VERSION 5.7 ;
  NOWIREEXTENSIONATPIN ON ;
  DIVIDERCHAR "/" ;
  BUSBITCHARS "[]" ;
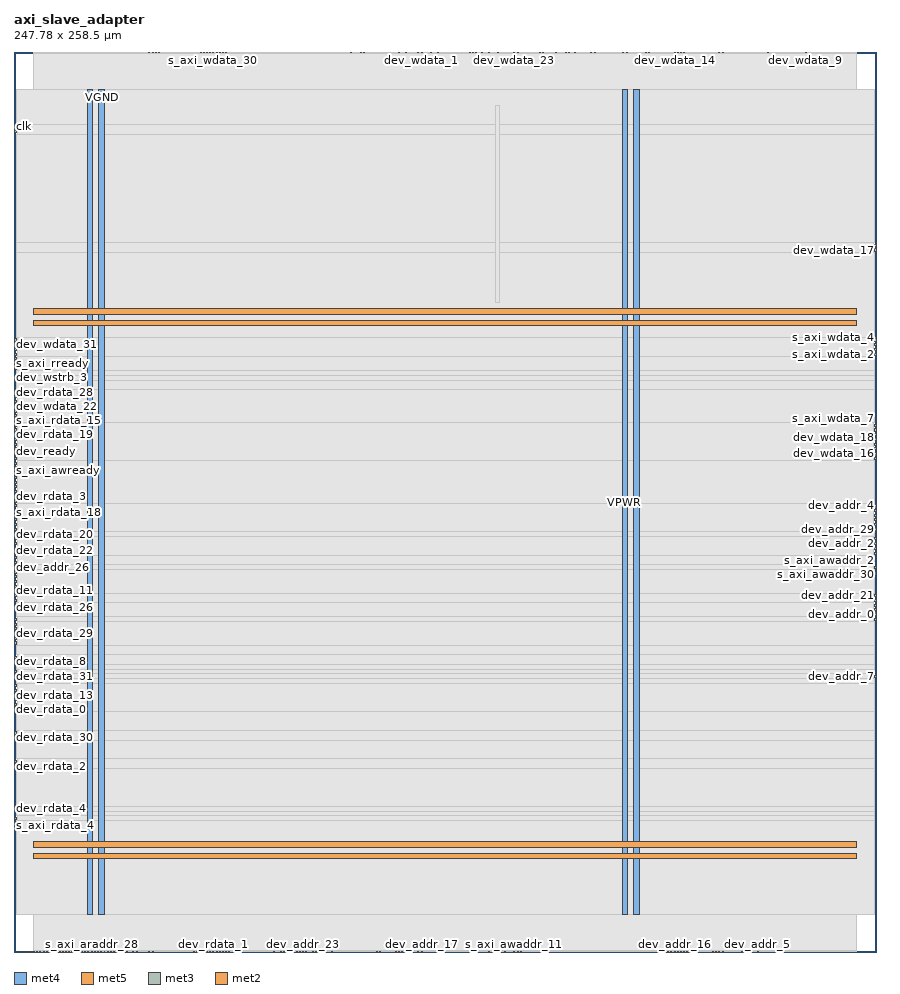
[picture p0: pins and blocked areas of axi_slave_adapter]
MACRO axi_slave_adapter
  CLASS BLOCK ;
  FOREIGN axi_slave_adapter ;
  ORIGIN 0.000 0.000 ;
  SIZE 247.780 BY 258.500 ;
  PIN VGND
    DIRECTION INOUT ;
    USE GROUND ;
    PORT
      LAYER met4 ;
        RECT 24.340 10.640 25.940 247.760 ;
    END
    PORT
      LAYER met4 ;
        RECT 177.940 10.640 179.540 247.760 ;
    END
    PORT
      LAYER met5 ;
        RECT 5.520 30.030 241.960 31.630 ;
    END
    PORT
      LAYER met5 ;
        RECT 5.520 183.210 241.960 184.810 ;
    END
  END VGND
  PIN VPWR
    DIRECTION INOUT ;
    USE POWER ;
    PORT
      LAYER met4 ;
        RECT 21.040 10.640 22.640 247.760 ;
    END
    PORT
      LAYER met4 ;
        RECT 174.640 10.640 176.240 247.760 ;
    END
    PORT
      LAYER met5 ;
        RECT 5.520 26.730 241.960 28.330 ;
    END
    PORT
      LAYER met5 ;
        RECT 5.520 179.910 241.960 181.510 ;
    END
  END VPWR
  PIN clk
    DIRECTION INPUT ;
    USE SIGNAL ;
    ANTENNAGATEAREA 1.286700 ;
    ANTENNADIFFAREA 0.434700 ;
    PORT
      LAYER met3 ;
        RECT 0.000 236.680 0.600 237.280 ;
    END
  END clk
  PIN dev_addr_0
    DIRECTION OUTPUT ;
    USE SIGNAL ;
    ANTENNAGATEAREA 0.434700 ;
    ANTENNADIFFAREA 1.137600 ;
    PORT
      LAYER met3 ;
        RECT 247.180 96.600 247.780 97.200 ;
    END
  END dev_addr_0
  PIN dev_addr_1
    DIRECTION OUTPUT ;
    USE SIGNAL ;
    ANTENNAGATEAREA 0.434700 ;
    ANTENNADIFFAREA 1.137600 ;
    PORT
      LAYER met2 ;
        RECT 200.650 0.000 200.930 0.280 ;
    END
  END dev_addr_1
  PIN dev_addr_10
    DIRECTION OUTPUT ;
    USE SIGNAL ;
    ANTENNAGATEAREA 0.434700 ;
    ANTENNADIFFAREA 1.137600 ;
    PORT
      LAYER met2 ;
        RECT 194.210 0.000 194.490 0.280 ;
    END
  END dev_addr_10
  PIN dev_addr_11
    DIRECTION OUTPUT ;
    USE SIGNAL ;
    ANTENNAGATEAREA 0.434700 ;
    ANTENNADIFFAREA 1.137600 ;
    PORT
      LAYER met2 ;
        RECT 140.850 0.000 141.130 0.280 ;
    END
  END dev_addr_11
  PIN dev_addr_12
    DIRECTION OUTPUT ;
    USE SIGNAL ;
    ANTENNAGATEAREA 0.434700 ;
    ANTENNADIFFAREA 1.137600 ;
    PORT
      LAYER met2 ;
        RECT 190.530 0.000 190.810 0.280 ;
    END
  END dev_addr_12
  PIN dev_addr_13
    DIRECTION OUTPUT ;
    USE SIGNAL ;
    ANTENNAGATEAREA 0.434700 ;
    ANTENNADIFFAREA 1.137600 ;
    PORT
      LAYER met2 ;
        RECT 74.610 0.000 74.890 0.280 ;
    END
  END dev_addr_13
  PIN dev_addr_14
    DIRECTION OUTPUT ;
    USE SIGNAL ;
    ANTENNAGATEAREA 0.434700 ;
    ANTENNADIFFAREA 1.137600 ;
    PORT
      LAYER met2 ;
        RECT 104.050 0.000 104.330 0.280 ;
    END
  END dev_addr_14
  PIN dev_addr_15
    DIRECTION OUTPUT ;
    USE SIGNAL ;
    ANTENNAGATEAREA 0.434700 ;
    ANTENNADIFFAREA 1.137600 ;
    PORT
      LAYER met2 ;
        RECT 136.250 0.000 136.530 0.280 ;
    END
  END dev_addr_15
  PIN dev_addr_16
    DIRECTION OUTPUT ;
    USE SIGNAL ;
    ANTENNAGATEAREA 0.434700 ;
    ANTENNADIFFAREA 1.137600 ;
    PORT
      LAYER met2 ;
        RECT 189.610 0.000 189.890 0.280 ;
    END
  END dev_addr_16
  PIN dev_addr_17
    DIRECTION OUTPUT ;
    USE SIGNAL ;
    ANTENNAGATEAREA 0.434700 ;
    ANTENNADIFFAREA 1.137600 ;
    PORT
      LAYER met2 ;
        RECT 116.930 0.000 117.210 0.280 ;
    END
  END dev_addr_17
  PIN dev_addr_18
    DIRECTION OUTPUT ;
    USE SIGNAL ;
    ANTENNAGATEAREA 0.434700 ;
    ANTENNADIFFAREA 1.137600 ;
    PORT
      LAYER met2 ;
        RECT 188.690 0.000 188.970 0.280 ;
    END
  END dev_addr_18
  PIN dev_addr_19
    DIRECTION OUTPUT ;
    USE SIGNAL ;
    ANTENNAGATEAREA 0.434700 ;
    ANTENNADIFFAREA 1.137600 ;
    PORT
      LAYER met2 ;
        RECT 203.410 0.000 203.690 0.280 ;
    END
  END dev_addr_19
  PIN dev_addr_2
    DIRECTION OUTPUT ;
    USE SIGNAL ;
    ANTENNAGATEAREA 0.434700 ;
    ANTENNADIFFAREA 1.137600 ;
    PORT
      LAYER met3 ;
        RECT 247.180 117.000 247.780 117.600 ;
    END
  END dev_addr_2
  PIN dev_addr_20
    DIRECTION OUTPUT ;
    USE SIGNAL ;
    ANTENNAGATEAREA 0.434700 ;
    ANTENNADIFFAREA 1.137600 ;
    PORT
      LAYER met2 ;
        RECT 111.410 0.000 111.690 0.280 ;
    END
  END dev_addr_20
  PIN dev_addr_21
    DIRECTION OUTPUT ;
    USE SIGNAL ;
    ANTENNAGATEAREA 0.434700 ;
    ANTENNADIFFAREA 1.137600 ;
    PORT
      LAYER met3 ;
        RECT 247.180 102.040 247.780 102.640 ;
    END
  END dev_addr_21
  PIN dev_addr_22
    DIRECTION OUTPUT ;
    USE SIGNAL ;
    ANTENNAGATEAREA 0.434700 ;
    ANTENNADIFFAREA 1.137600 ;
    PORT
      LAYER met2 ;
        RECT 122.450 0.000 122.730 0.280 ;
    END
  END dev_addr_22
  PIN dev_addr_23
    DIRECTION OUTPUT ;
    USE SIGNAL ;
    ANTENNAGATEAREA 0.434700 ;
    ANTENNADIFFAREA 1.137600 ;
    PORT
      LAYER met2 ;
        RECT 82.890 0.000 83.170 0.280 ;
    END
  END dev_addr_23
  PIN dev_addr_24
    DIRECTION OUTPUT ;
    USE SIGNAL ;
    ANTENNAGATEAREA 0.434700 ;
    ANTENNADIFFAREA 1.137600 ;
    PORT
      LAYER met2 ;
        RECT 76.450 0.000 76.730 0.280 ;
    END
  END dev_addr_24
  PIN dev_addr_25
    DIRECTION OUTPUT ;
    USE SIGNAL ;
    ANTENNAGATEAREA 0.434700 ;
    ANTENNADIFFAREA 1.137600 ;
    PORT
      LAYER met2 ;
        RECT 86.570 0.000 86.850 0.280 ;
    END
  END dev_addr_25
  PIN dev_addr_26
    DIRECTION OUTPUT ;
    USE SIGNAL ;
    ANTENNAGATEAREA 0.434700 ;
    ANTENNADIFFAREA 1.137600 ;
    PORT
      LAYER met3 ;
        RECT 0.000 110.200 0.600 110.800 ;
    END
  END dev_addr_26
  PIN dev_addr_27
    DIRECTION OUTPUT ;
    USE SIGNAL ;
    ANTENNAGATEAREA 0.434700 ;
    ANTENNADIFFAREA 1.137600 ;
    PORT
      LAYER met2 ;
        RECT 193.290 0.000 193.570 0.280 ;
    END
  END dev_addr_27
  PIN dev_addr_28
    DIRECTION OUTPUT ;
    USE SIGNAL ;
    ANTENNAGATEAREA 0.434700 ;
    ANTENNADIFFAREA 1.137600 ;
    PORT
      LAYER met3 ;
        RECT 0.000 123.800 0.600 124.400 ;
    END
  END dev_addr_28
  PIN dev_addr_29
    DIRECTION OUTPUT ;
    USE SIGNAL ;
    ANTENNAGATEAREA 0.434700 ;
    ANTENNADIFFAREA 1.137600 ;
    PORT
      LAYER met3 ;
        RECT 247.180 121.080 247.780 121.680 ;
    END
  END dev_addr_29
  PIN dev_addr_3
    DIRECTION OUTPUT ;
    USE SIGNAL ;
    ANTENNAGATEAREA 0.434700 ;
    ANTENNADIFFAREA 1.137600 ;
    PORT
      LAYER met3 ;
        RECT 247.180 100.680 247.780 101.280 ;
    END
  END dev_addr_3
  PIN dev_addr_30
    DIRECTION OUTPUT ;
    USE SIGNAL ;
    ANTENNAGATEAREA 0.434700 ;
    ANTENNADIFFAREA 1.137600 ;
    PORT
      LAYER met3 ;
        RECT 247.180 115.640 247.780 116.240 ;
    END
  END dev_addr_30
  PIN dev_addr_31
    DIRECTION OUTPUT ;
    USE SIGNAL ;
    ANTENNAGATEAREA 0.434700 ;
    ANTENNADIFFAREA 1.137600 ;
    PORT
      LAYER met3 ;
        RECT 247.180 126.520 247.780 127.120 ;
    END
  END dev_addr_31
  PIN dev_addr_4
    DIRECTION OUTPUT ;
    USE SIGNAL ;
    ANTENNAGATEAREA 0.434700 ;
    ANTENNADIFFAREA 1.137600 ;
    PORT
      LAYER met3 ;
        RECT 247.180 127.880 247.780 128.480 ;
    END
  END dev_addr_4
  PIN dev_addr_5
    DIRECTION OUTPUT ;
    USE SIGNAL ;
    ANTENNAGATEAREA 0.434700 ;
    ANTENNADIFFAREA 1.137600 ;
    PORT
      LAYER met2 ;
        RECT 213.530 0.000 213.810 0.280 ;
    END
  END dev_addr_5
  PIN dev_addr_6
    DIRECTION OUTPUT ;
    USE SIGNAL ;
    ANTENNAGATEAREA 0.434700 ;
    ANTENNADIFFAREA 1.137600 ;
    PORT
      LAYER met2 ;
        RECT 144.530 0.000 144.810 0.280 ;
    END
  END dev_addr_6
  PIN dev_addr_7
    DIRECTION OUTPUT ;
    USE SIGNAL ;
    ANTENNAGATEAREA 0.434700 ;
    ANTENNADIFFAREA 1.137600 ;
    PORT
      LAYER met3 ;
        RECT 247.180 78.920 247.780 79.520 ;
    END
  END dev_addr_7
  PIN dev_addr_8
    DIRECTION OUTPUT ;
    USE SIGNAL ;
    ANTENNAGATEAREA 0.434700 ;
    ANTENNADIFFAREA 1.137600 ;
    PORT
      LAYER met2 ;
        RECT 110.490 0.000 110.770 0.280 ;
    END
  END dev_addr_8
  PIN dev_addr_9
    DIRECTION OUTPUT ;
    USE SIGNAL ;
    ANTENNAGATEAREA 0.434700 ;
    ANTENNADIFFAREA 1.137600 ;
    PORT
      LAYER met2 ;
        RECT 77.370 0.000 77.650 0.280 ;
    END
  END dev_addr_9
  PIN dev_rdata_0
    DIRECTION INPUT ;
    USE SIGNAL ;
    ANTENNAGATEAREA 0.647700 ;
    ANTENNADIFFAREA 0.434700 ;
    PORT
      LAYER met3 ;
        RECT 0.000 69.400 0.600 70.000 ;
    END
  END dev_rdata_0
  PIN dev_rdata_1
    DIRECTION INPUT ;
    USE SIGNAL ;
    ANTENNAGATEAREA 0.647700 ;
    ANTENNADIFFAREA 0.434700 ;
    PORT
      LAYER met2 ;
        RECT 57.130 0.000 57.410 0.280 ;
    END
  END dev_rdata_1
  PIN dev_rdata_10
    DIRECTION INPUT ;
    USE SIGNAL ;
    ANTENNAGATEAREA 0.647700 ;
    ANTENNADIFFAREA 0.434700 ;
    PORT
      LAYER met2 ;
        RECT 58.970 0.000 59.250 0.280 ;
    END
  END dev_rdata_10
  PIN dev_rdata_11
    DIRECTION INPUT ;
    USE SIGNAL ;
    ANTENNAGATEAREA 0.647700 ;
    ANTENNADIFFAREA 0.434700 ;
    PORT
      LAYER met3 ;
        RECT 0.000 103.400 0.600 104.000 ;
    END
  END dev_rdata_11
  PIN dev_rdata_12
    DIRECTION INPUT ;
    USE SIGNAL ;
    ANTENNAGATEAREA 0.647700 ;
    ANTENNADIFFAREA 0.434700 ;
    PORT
      LAYER met3 ;
        RECT 0.000 125.160 0.600 125.760 ;
    END
  END dev_rdata_12
  PIN dev_rdata_13
    DIRECTION INPUT ;
    USE SIGNAL ;
    ANTENNAGATEAREA 0.647700 ;
    ANTENNADIFFAREA 0.434700 ;
    PORT
      LAYER met3 ;
        RECT 0.000 73.480 0.600 74.080 ;
    END
  END dev_rdata_13
  PIN dev_rdata_14
    DIRECTION INPUT ;
    USE SIGNAL ;
    ANTENNAGATEAREA 0.647700 ;
    ANTENNADIFFAREA 0.434700 ;
    PORT
      LAYER met2 ;
        RECT 35.050 0.000 35.330 0.280 ;
    END
  END dev_rdata_14
  PIN dev_rdata_15
    DIRECTION INPUT ;
    USE SIGNAL ;
    ANTENNAGATEAREA 0.647700 ;
    ANTENNADIFFAREA 0.434700 ;
    PORT
      LAYER met3 ;
        RECT 0.000 149.640 0.600 150.240 ;
    END
  END dev_rdata_15
  PIN dev_rdata_16
    DIRECTION INPUT ;
    USE SIGNAL ;
    ANTENNAGATEAREA 0.647700 ;
    ANTENNADIFFAREA 0.434700 ;
    PORT
      LAYER met2 ;
        RECT 51.610 0.000 51.890 0.280 ;
    END
  END dev_rdata_16
  PIN dev_rdata_17
    DIRECTION INPUT ;
    USE SIGNAL ;
    ANTENNAGATEAREA 0.647700 ;
    ANTENNADIFFAREA 0.434700 ;
    PORT
      LAYER met2 ;
        RECT 21.250 0.000 21.530 0.280 ;
    END
  END dev_rdata_17
  PIN dev_rdata_18
    DIRECTION INPUT ;
    USE SIGNAL ;
    ANTENNAGATEAREA 0.647700 ;
    ANTENNADIFFAREA 0.434700 ;
    PORT
      LAYER met3 ;
        RECT 0.000 126.520 0.600 127.120 ;
    END
  END dev_rdata_18
  PIN dev_rdata_19
    DIRECTION INPUT ;
    USE SIGNAL ;
    ANTENNAGATEAREA 0.647700 ;
    ANTENNADIFFAREA 0.434700 ;
    PORT
      LAYER met3 ;
        RECT 0.000 148.280 0.600 148.880 ;
    END
  END dev_rdata_19
  PIN dev_rdata_2
    DIRECTION INPUT ;
    USE SIGNAL ;
    ANTENNAGATEAREA 0.647700 ;
    ANTENNADIFFAREA 0.434700 ;
    PORT
      LAYER met3 ;
        RECT 0.000 53.080 0.600 53.680 ;
    END
  END dev_rdata_2
  PIN dev_rdata_20
    DIRECTION INPUT ;
    USE SIGNAL ;
    ANTENNAGATEAREA 0.647700 ;
    ANTENNADIFFAREA 0.434700 ;
    PORT
      LAYER met3 ;
        RECT 0.000 119.720 0.600 120.320 ;
    END
  END dev_rdata_20
  PIN dev_rdata_21
    DIRECTION INPUT ;
    USE SIGNAL ;
    ANTENNAGATEAREA 0.647700 ;
    ANTENNADIFFAREA 0.434700 ;
    PORT
      LAYER met2 ;
        RECT 39.650 0.000 39.930 0.280 ;
    END
  END dev_rdata_21
  PIN dev_rdata_22
    DIRECTION INPUT ;
    USE SIGNAL ;
    ANTENNAGATEAREA 0.647700 ;
    ANTENNADIFFAREA 0.434700 ;
    PORT
      LAYER met3 ;
        RECT 0.000 117.000 0.600 117.600 ;
    END
  END dev_rdata_22
  PIN dev_rdata_23
    DIRECTION INPUT ;
    USE SIGNAL ;
    ANTENNAGATEAREA 0.647700 ;
    ANTENNADIFFAREA 0.434700 ;
    PORT
      LAYER met3 ;
        RECT 0.000 106.120 0.600 106.720 ;
    END
  END dev_rdata_23
  PIN dev_rdata_24
    DIRECTION INPUT ;
    USE SIGNAL ;
    ANTENNAGATEAREA 0.647700 ;
    ANTENNADIFFAREA 0.434700 ;
    PORT
      LAYER met2 ;
        RECT 59.890 0.000 60.170 0.280 ;
    END
  END dev_rdata_24
  PIN dev_rdata_25
    DIRECTION INPUT ;
    USE SIGNAL ;
    ANTENNAGATEAREA 0.647700 ;
    ANTENNADIFFAREA 0.434700 ;
    PORT
      LAYER met3 ;
        RECT 0.000 74.840 0.600 75.440 ;
    END
  END dev_rdata_25
  PIN dev_rdata_26
    DIRECTION INPUT ;
    USE SIGNAL ;
    ANTENNAGATEAREA 0.647700 ;
    ANTENNADIFFAREA 0.434700 ;
    PORT
      LAYER met3 ;
        RECT 0.000 100.680 0.600 101.280 ;
    END
  END dev_rdata_26
  PIN dev_rdata_27
    DIRECTION INPUT ;
    USE SIGNAL ;
    ANTENNAGATEAREA 0.647700 ;
    ANTENNADIFFAREA 0.434700 ;
    PORT
      LAYER met3 ;
        RECT 0.000 115.640 0.600 116.240 ;
    END
  END dev_rdata_27
  PIN dev_rdata_28
    DIRECTION INPUT ;
    USE SIGNAL ;
    ANTENNAGATEAREA 0.647700 ;
    ANTENNADIFFAREA 0.434700 ;
    PORT
      LAYER met3 ;
        RECT 0.000 160.520 0.600 161.120 ;
    END
  END dev_rdata_28
  PIN dev_rdata_29
    DIRECTION INPUT ;
    USE SIGNAL ;
    ANTENNAGATEAREA 0.647700 ;
    ANTENNADIFFAREA 0.434700 ;
    PORT
      LAYER met3 ;
        RECT 0.000 91.160 0.600 91.760 ;
    END
  END dev_rdata_29
  PIN dev_rdata_3
    DIRECTION INPUT ;
    USE SIGNAL ;
    ANTENNAGATEAREA 0.647700 ;
    ANTENNADIFFAREA 0.434700 ;
    PORT
      LAYER met3 ;
        RECT 0.000 130.600 0.600 131.200 ;
    END
  END dev_rdata_3
  PIN dev_rdata_30
    DIRECTION INPUT ;
    USE SIGNAL ;
    ANTENNAGATEAREA 0.647700 ;
    ANTENNADIFFAREA 0.434700 ;
    PORT
      LAYER met3 ;
        RECT 0.000 61.240 0.600 61.840 ;
    END
  END dev_rdata_30
  PIN dev_rdata_31
    DIRECTION INPUT ;
    USE SIGNAL ;
    ANTENNAGATEAREA 0.647700 ;
    ANTENNADIFFAREA 0.434700 ;
    PORT
      LAYER met3 ;
        RECT 0.000 78.920 0.600 79.520 ;
    END
  END dev_rdata_31
  PIN dev_rdata_4
    DIRECTION INPUT ;
    USE SIGNAL ;
    ANTENNAGATEAREA 0.647700 ;
    ANTENNADIFFAREA 0.434700 ;
    PORT
      LAYER met3 ;
        RECT 0.000 40.840 0.600 41.440 ;
    END
  END dev_rdata_4
  PIN dev_rdata_5
    DIRECTION INPUT ;
    USE SIGNAL ;
    ANTENNAGATEAREA 0.647700 ;
    ANTENNADIFFAREA 0.434700 ;
    PORT
      LAYER met2 ;
        RECT 56.210 0.000 56.490 0.280 ;
    END
  END dev_rdata_5
  PIN dev_rdata_6
    DIRECTION INPUT ;
    USE SIGNAL ;
    ANTENNAGATEAREA 0.647700 ;
    ANTENNADIFFAREA 0.434700 ;
    PORT
      LAYER met3 ;
        RECT 0.000 88.440 0.600 89.040 ;
    END
  END dev_rdata_6
  PIN dev_rdata_7
    DIRECTION INPUT ;
    USE SIGNAL ;
    ANTENNAGATEAREA 0.647700 ;
    ANTENNADIFFAREA 0.434700 ;
    PORT
      LAYER met3 ;
        RECT 0.000 111.560 0.600 112.160 ;
    END
  END dev_rdata_7
  PIN dev_rdata_8
    DIRECTION INPUT ;
    USE SIGNAL ;
    ANTENNAGATEAREA 0.647700 ;
    ANTENNADIFFAREA 0.434700 ;
    PORT
      LAYER met3 ;
        RECT 0.000 83.000 0.600 83.600 ;
    END
  END dev_rdata_8
  PIN dev_rdata_9
    DIRECTION INPUT ;
    USE SIGNAL ;
    ANTENNAGATEAREA 0.647700 ;
    ANTENNADIFFAREA 0.434700 ;
    PORT
      LAYER met3 ;
        RECT 0.000 93.880 0.600 94.480 ;
    END
  END dev_rdata_9
  PIN dev_ready
    DIRECTION INPUT ;
    USE SIGNAL ;
    ANTENNAGATEAREA 0.647700 ;
    ANTENNADIFFAREA 0.434700 ;
    PORT
      LAYER met3 ;
        RECT 0.000 145.560 0.600 146.160 ;
    END
  END dev_ready
  PIN dev_req
    DIRECTION OUTPUT ;
    USE SIGNAL ;
    ANTENNAGATEAREA 0.434700 ;
    ANTENNADIFFAREA 1.137600 ;
    PORT
      LAYER met3 ;
        RECT 247.180 118.360 247.780 118.960 ;
    END
  END dev_req
  PIN dev_wdata_0
    DIRECTION OUTPUT ;
    USE SIGNAL ;
    ANTENNAGATEAREA 0.434700 ;
    ANTENNADIFFAREA 1.137600 ;
    PORT
      LAYER met2 ;
        RECT 174.890 258.220 175.170 258.500 ;
    END
  END dev_wdata_0
  PIN dev_wdata_1
    DIRECTION OUTPUT ;
    USE SIGNAL ;
    ANTENNAGATEAREA 0.434700 ;
    ANTENNADIFFAREA 1.137600 ;
    PORT
      LAYER met2 ;
        RECT 116.930 258.220 117.210 258.500 ;
    END
  END dev_wdata_1
  PIN dev_wdata_10
    DIRECTION OUTPUT ;
    USE SIGNAL ;
    ANTENNAGATEAREA 0.434700 ;
    ANTENNADIFFAREA 1.137600 ;
    PORT
      LAYER met2 ;
        RECT 202.490 258.220 202.770 258.500 ;
    END
  END dev_wdata_10
  PIN dev_wdata_11
    DIRECTION OUTPUT ;
    USE SIGNAL ;
    ANTENNAGATEAREA 0.434700 ;
    ANTENNADIFFAREA 1.137600 ;
    PORT
      LAYER met2 ;
        RECT 121.530 258.220 121.810 258.500 ;
    END
  END dev_wdata_11
  PIN dev_wdata_12
    DIRECTION OUTPUT ;
    USE SIGNAL ;
    ANTENNAGATEAREA 0.434700 ;
    ANTENNADIFFAREA 1.137600 ;
    PORT
      LAYER met3 ;
        RECT 247.180 141.480 247.780 142.080 ;
    END
  END dev_wdata_12
  PIN dev_wdata_13
    DIRECTION OUTPUT ;
    USE SIGNAL ;
    ANTENNAGATEAREA 0.434700 ;
    ANTENNADIFFAREA 1.137600 ;
    PORT
      LAYER met2 ;
        RECT 136.250 258.220 136.530 258.500 ;
    END
  END dev_wdata_13
  PIN dev_wdata_14
    DIRECTION OUTPUT ;
    USE SIGNAL ;
    ANTENNAGATEAREA 0.434700 ;
    ANTENNADIFFAREA 1.137600 ;
    PORT
      LAYER met2 ;
        RECT 189.610 258.220 189.890 258.500 ;
    END
  END dev_wdata_14
  PIN dev_wdata_15
    DIRECTION OUTPUT ;
    USE SIGNAL ;
    ANTENNAGATEAREA 0.434700 ;
    ANTENNADIFFAREA 1.137600 ;
    PORT
      LAYER met2 ;
        RECT 150.970 258.220 151.250 258.500 ;
    END
  END dev_wdata_15
  PIN dev_wdata_16
    DIRECTION OUTPUT ;
    USE SIGNAL ;
    ANTENNAGATEAREA 0.434700 ;
    ANTENNADIFFAREA 1.137600 ;
    PORT
      LAYER met3 ;
        RECT 247.180 142.840 247.780 143.440 ;
    END
  END dev_wdata_16
  PIN dev_wdata_17
    DIRECTION OUTPUT ;
    USE SIGNAL ;
    ANTENNAGATEAREA 0.434700 ;
    ANTENNADIFFAREA 1.137600 ;
    PORT
      LAYER met3 ;
        RECT 247.180 201.320 247.780 201.920 ;
    END
  END dev_wdata_17
  PIN dev_wdata_18
    DIRECTION OUTPUT ;
    USE SIGNAL ;
    ANTENNAGATEAREA 0.434700 ;
    ANTENNADIFFAREA 1.137600 ;
    PORT
      LAYER met3 ;
        RECT 247.180 145.560 247.780 146.160 ;
    END
  END dev_wdata_18
  PIN dev_wdata_19
    DIRECTION OUTPUT ;
    USE SIGNAL ;
    ANTENNAGATEAREA 0.434700 ;
    ANTENNADIFFAREA 1.137600 ;
    PORT
      LAYER met2 ;
        RECT 165.690 258.220 165.970 258.500 ;
    END
  END dev_wdata_19
  PIN dev_wdata_2
    DIRECTION OUTPUT ;
    USE SIGNAL ;
    ANTENNAGATEAREA 0.434700 ;
    ANTENNADIFFAREA 1.137600 ;
    PORT
      LAYER met3 ;
        RECT 247.180 172.760 247.780 173.360 ;
    END
  END dev_wdata_2
  PIN dev_wdata_20
    DIRECTION OUTPUT ;
    USE SIGNAL ;
    ANTENNAGATEAREA 0.434700 ;
    ANTENNADIFFAREA 1.137600 ;
    PORT
      LAYER met2 ;
        RECT 134.410 258.220 134.690 258.500 ;
    END
  END dev_wdata_20
  PIN dev_wdata_21
    DIRECTION OUTPUT ;
    USE SIGNAL ;
    ANTENNAGATEAREA 0.434700 ;
    ANTENNADIFFAREA 1.137600 ;
    PORT
      LAYER met2 ;
        RECT 155.570 258.220 155.850 258.500 ;
    END
  END dev_wdata_21
  PIN dev_wdata_22
    DIRECTION OUTPUT ;
    USE SIGNAL ;
    ANTENNAGATEAREA 0.434700 ;
    ANTENNADIFFAREA 1.137600 ;
    PORT
      LAYER met3 ;
        RECT 0.000 156.440 0.600 157.040 ;
    END
  END dev_wdata_22
  PIN dev_wdata_23
    DIRECTION OUTPUT ;
    USE SIGNAL ;
    ANTENNAGATEAREA 0.434700 ;
    ANTENNADIFFAREA 1.137600 ;
    PORT
      LAYER met2 ;
        RECT 143.610 258.220 143.890 258.500 ;
    END
  END dev_wdata_23
  PIN dev_wdata_24
    DIRECTION OUTPUT ;
    USE SIGNAL ;
    ANTENNAGATEAREA 0.434700 ;
    ANTENNADIFFAREA 1.137600 ;
    PORT
      LAYER met2 ;
        RECT 130.730 258.220 131.010 258.500 ;
    END
  END dev_wdata_24
  PIN dev_wdata_25
    DIRECTION OUTPUT ;
    USE SIGNAL ;
    ANTENNAGATEAREA 0.434700 ;
    ANTENNADIFFAREA 1.137600 ;
    PORT
      LAYER met2 ;
        RECT 181.330 258.220 181.610 258.500 ;
    END
  END dev_wdata_25
  PIN dev_wdata_26
    DIRECTION OUTPUT ;
    USE SIGNAL ;
    ANTENNAGATEAREA 0.434700 ;
    ANTENNADIFFAREA 1.137600 ;
    PORT
      LAYER met2 ;
        RECT 96.690 258.220 96.970 258.500 ;
    END
  END dev_wdata_26
  PIN dev_wdata_27
    DIRECTION OUTPUT ;
    USE SIGNAL ;
    ANTENNAGATEAREA 0.434700 ;
    ANTENNADIFFAREA 1.137600 ;
    PORT
      LAYER met2 ;
        RECT 159.250 258.220 159.530 258.500 ;
    END
  END dev_wdata_27
  PIN dev_wdata_28
    DIRECTION OUTPUT ;
    USE SIGNAL ;
    ANTENNAGATEAREA 0.434700 ;
    ANTENNADIFFAREA 1.137600 ;
    PORT
      LAYER met2 ;
        RECT 54.370 258.220 54.650 258.500 ;
    END
  END dev_wdata_28
  PIN dev_wdata_29
    DIRECTION OUTPUT ;
    USE SIGNAL ;
    ANTENNAGATEAREA 0.434700 ;
    ANTENNADIFFAREA 1.137600 ;
    PORT
      LAYER met2 ;
        RECT 58.970 258.220 59.250 258.500 ;
    END
  END dev_wdata_29
  PIN dev_wdata_3
    DIRECTION OUTPUT ;
    USE SIGNAL ;
    ANTENNAGATEAREA 0.434700 ;
    ANTENNADIFFAREA 1.137600 ;
    PORT
      LAYER met3 ;
        RECT 0.000 175.480 0.600 176.080 ;
    END
  END dev_wdata_3
  PIN dev_wdata_30
    DIRECTION OUTPUT ;
    USE SIGNAL ;
    ANTENNAGATEAREA 0.434700 ;
    ANTENNADIFFAREA 1.137600 ;
    PORT
      LAYER met2 ;
        RECT 40.570 258.220 40.850 258.500 ;
    END
  END dev_wdata_30
  PIN dev_wdata_31
    DIRECTION OUTPUT ;
    USE SIGNAL ;
    ANTENNAGATEAREA 0.434700 ;
    ANTENNADIFFAREA 1.137600 ;
    PORT
      LAYER met3 ;
        RECT 0.000 174.120 0.600 174.720 ;
    END
  END dev_wdata_31
  PIN dev_wdata_4
    DIRECTION OUTPUT ;
    USE SIGNAL ;
    ANTENNAGATEAREA 0.434700 ;
    ANTENNADIFFAREA 1.137600 ;
    PORT
      LAYER met3 ;
        RECT 247.180 175.480 247.780 176.080 ;
    END
  END dev_wdata_4
  PIN dev_wdata_5
    DIRECTION OUTPUT ;
    USE SIGNAL ;
    ANTENNAGATEAREA 0.434700 ;
    ANTENNADIFFAREA 1.137600 ;
    PORT
      LAYER met2 ;
        RECT 191.450 258.220 191.730 258.500 ;
    END
  END dev_wdata_5
  PIN dev_wdata_6
    DIRECTION OUTPUT ;
    USE SIGNAL ;
    ANTENNAGATEAREA 0.434700 ;
    ANTENNADIFFAREA 1.137600 ;
    PORT
      LAYER met2 ;
        RECT 112.330 258.220 112.610 258.500 ;
    END
  END dev_wdata_6
  PIN dev_wdata_7
    DIRECTION OUTPUT ;
    USE SIGNAL ;
    ANTENNAGATEAREA 0.434700 ;
    ANTENNADIFFAREA 1.137600 ;
    PORT
      LAYER met3 ;
        RECT 247.180 149.640 247.780 150.240 ;
    END
  END dev_wdata_7
  PIN dev_wdata_8
    DIRECTION OUTPUT ;
    USE SIGNAL ;
    ANTENNAGATEAREA 0.434700 ;
    ANTENNADIFFAREA 1.137600 ;
    PORT
      LAYER met2 ;
        RECT 60.810 258.220 61.090 258.500 ;
    END
  END dev_wdata_8
  PIN dev_wdata_9
    DIRECTION OUTPUT ;
    USE SIGNAL ;
    ANTENNAGATEAREA 0.434700 ;
    ANTENNADIFFAREA 1.137600 ;
    PORT
      LAYER met2 ;
        RECT 227.330 258.220 227.610 258.500 ;
    END
  END dev_wdata_9
  PIN dev_wstrb_0
    DIRECTION OUTPUT ;
    USE SIGNAL ;
    ANTENNAGATEAREA 0.434700 ;
    ANTENNADIFFAREA 1.137600 ;
    PORT
      LAYER met2 ;
        RECT 41.490 258.220 41.770 258.500 ;
    END
  END dev_wstrb_0
  PIN dev_wstrb_1
    DIRECTION OUTPUT ;
    USE SIGNAL ;
    ANTENNAGATEAREA 0.434700 ;
    ANTENNADIFFAREA 1.137600 ;
    PORT
      LAYER met2 ;
        RECT 39.650 258.220 39.930 258.500 ;
    END
  END dev_wstrb_1
  PIN dev_wstrb_2
    DIRECTION OUTPUT ;
    USE SIGNAL ;
    ANTENNAGATEAREA 0.434700 ;
    ANTENNADIFFAREA 1.137600 ;
    PORT
      LAYER met2 ;
        RECT 38.730 258.220 39.010 258.500 ;
    END
  END dev_wstrb_2
  PIN dev_wstrb_3
    DIRECTION OUTPUT ;
    USE SIGNAL ;
    ANTENNAGATEAREA 0.434700 ;
    ANTENNADIFFAREA 1.137600 ;
    PORT
      LAYER met3 ;
        RECT 0.000 164.600 0.600 165.200 ;
    END
  END dev_wstrb_3
  PIN rst_n
    DIRECTION INPUT ;
    USE SIGNAL ;
    ANTENNAGATEAREA 0.647700 ;
    ANTENNADIFFAREA 0.434700 ;
    PORT
      LAYER met3 ;
        RECT 0.000 235.320 0.600 235.920 ;
    END
  END rst_n
  PIN s_axi_araddr_0
    DIRECTION INPUT ;
    USE SIGNAL ;
    PORT
      LAYER met2 ;
        RECT 1.930 0.000 2.210 0.280 ;
    END
  END s_axi_araddr_0
  PIN s_axi_araddr_1
    DIRECTION INPUT ;
    USE SIGNAL ;
    PORT
      LAYER met2 ;
        RECT 2.850 0.000 3.130 0.280 ;
    END
  END s_axi_araddr_1
  PIN s_axi_araddr_10
    DIRECTION INPUT ;
    USE SIGNAL ;
    PORT
      LAYER met2 ;
        RECT 3.770 0.000 4.050 0.280 ;
    END
  END s_axi_araddr_10
  PIN s_axi_araddr_11
    DIRECTION INPUT ;
    USE SIGNAL ;
    PORT
      LAYER met2 ;
        RECT 4.690 0.000 4.970 0.280 ;
    END
  END s_axi_araddr_11
  PIN s_axi_araddr_12
    DIRECTION INPUT ;
    USE SIGNAL ;
    PORT
      LAYER met2 ;
        RECT 5.610 0.000 5.890 0.280 ;
    END
  END s_axi_araddr_12
  PIN s_axi_araddr_13
    DIRECTION INPUT ;
    USE SIGNAL ;
    PORT
      LAYER met2 ;
        RECT 6.530 0.000 6.810 0.280 ;
    END
  END s_axi_araddr_13
  PIN s_axi_araddr_14
    DIRECTION INPUT ;
    USE SIGNAL ;
    PORT
      LAYER met2 ;
        RECT 7.450 0.000 7.730 0.280 ;
    END
  END s_axi_araddr_14
  PIN s_axi_araddr_15
    DIRECTION INPUT ;
    USE SIGNAL ;
    PORT
      LAYER met2 ;
        RECT 8.370 0.000 8.650 0.280 ;
    END
  END s_axi_araddr_15
  PIN s_axi_araddr_16
    DIRECTION INPUT ;
    USE SIGNAL ;
    PORT
      LAYER met2 ;
        RECT 9.290 0.000 9.570 0.280 ;
    END
  END s_axi_araddr_16
  PIN s_axi_araddr_17
    DIRECTION INPUT ;
    USE SIGNAL ;
    PORT
      LAYER met2 ;
        RECT 10.210 0.000 10.490 0.280 ;
    END
  END s_axi_araddr_17
  PIN s_axi_araddr_18
    DIRECTION INPUT ;
    USE SIGNAL ;
    PORT
      LAYER met2 ;
        RECT 11.130 0.000 11.410 0.280 ;
    END
  END s_axi_araddr_18
  PIN s_axi_araddr_19
    DIRECTION INPUT ;
    USE SIGNAL ;
    PORT
      LAYER met2 ;
        RECT 12.050 0.000 12.330 0.280 ;
    END
  END s_axi_araddr_19
  PIN s_axi_araddr_2
    DIRECTION INPUT ;
    USE SIGNAL ;
    PORT
      LAYER met2 ;
        RECT 12.970 0.000 13.250 0.280 ;
    END
  END s_axi_araddr_2
  PIN s_axi_araddr_20
    DIRECTION INPUT ;
    USE SIGNAL ;
    PORT
      LAYER met2 ;
        RECT 13.890 0.000 14.170 0.280 ;
    END
  END s_axi_araddr_20
  PIN s_axi_araddr_21
    DIRECTION INPUT ;
    USE SIGNAL ;
    PORT
      LAYER met2 ;
        RECT 14.810 0.000 15.090 0.280 ;
    END
  END s_axi_araddr_21
  PIN s_axi_araddr_22
    DIRECTION INPUT ;
    USE SIGNAL ;
    PORT
      LAYER met2 ;
        RECT 15.730 0.000 16.010 0.280 ;
    END
  END s_axi_araddr_22
  PIN s_axi_araddr_23
    DIRECTION INPUT ;
    USE SIGNAL ;
    PORT
      LAYER met2 ;
        RECT 16.650 0.000 16.930 0.280 ;
    END
  END s_axi_araddr_23
  PIN s_axi_araddr_24
    DIRECTION INPUT ;
    USE SIGNAL ;
    PORT
      LAYER met2 ;
        RECT 17.570 0.000 17.850 0.280 ;
    END
  END s_axi_araddr_24
  PIN s_axi_araddr_25
    DIRECTION INPUT ;
    USE SIGNAL ;
    PORT
      LAYER met2 ;
        RECT 18.490 0.000 18.770 0.280 ;
    END
  END s_axi_araddr_25
  PIN s_axi_araddr_26
    DIRECTION INPUT ;
    USE SIGNAL ;
    PORT
      LAYER met2 ;
        RECT 19.410 0.000 19.690 0.280 ;
    END
  END s_axi_araddr_26
  PIN s_axi_araddr_27
    DIRECTION INPUT ;
    USE SIGNAL ;
    PORT
      LAYER met2 ;
        RECT 23.090 0.000 23.370 0.280 ;
    END
  END s_axi_araddr_27
  PIN s_axi_araddr_28
    DIRECTION INPUT ;
    USE SIGNAL ;
    PORT
      LAYER met2 ;
        RECT 22.170 0.000 22.450 0.280 ;
    END
  END s_axi_araddr_28
  PIN s_axi_araddr_29
    DIRECTION INPUT ;
    USE SIGNAL ;
    PORT
      LAYER met2 ;
        RECT 24.930 0.000 25.210 0.280 ;
    END
  END s_axi_araddr_29
  PIN s_axi_araddr_3
    DIRECTION INPUT ;
    USE SIGNAL ;
    PORT
      LAYER met2 ;
        RECT 24.010 0.000 24.290 0.280 ;
    END
  END s_axi_araddr_3
  PIN s_axi_araddr_30
    DIRECTION INPUT ;
    USE SIGNAL ;
    PORT
      LAYER met2 ;
        RECT 26.770 0.000 27.050 0.280 ;
    END
  END s_axi_araddr_30
  PIN s_axi_araddr_31
    DIRECTION INPUT ;
    USE SIGNAL ;
    PORT
      LAYER met2 ;
        RECT 25.850 0.000 26.130 0.280 ;
    END
  END s_axi_araddr_31
  PIN s_axi_araddr_4
    DIRECTION INPUT ;
    USE SIGNAL ;
    PORT
      LAYER met2 ;
        RECT 28.610 0.000 28.890 0.280 ;
    END
  END s_axi_araddr_4
  PIN s_axi_araddr_5
    DIRECTION INPUT ;
    USE SIGNAL ;
    PORT
      LAYER met2 ;
        RECT 27.690 0.000 27.970 0.280 ;
    END
  END s_axi_araddr_5
  PIN s_axi_araddr_6
    DIRECTION INPUT ;
    USE SIGNAL ;
    PORT
      LAYER met2 ;
        RECT 30.450 0.000 30.730 0.280 ;
    END
  END s_axi_araddr_6
  PIN s_axi_araddr_7
    DIRECTION INPUT ;
    USE SIGNAL ;
    PORT
      LAYER met2 ;
        RECT 29.530 0.000 29.810 0.280 ;
    END
  END s_axi_araddr_7
  PIN s_axi_araddr_8
    DIRECTION INPUT ;
    USE SIGNAL ;
    PORT
      LAYER met2 ;
        RECT 32.290 0.000 32.570 0.280 ;
    END
  END s_axi_araddr_8
  PIN s_axi_araddr_9
    DIRECTION INPUT ;
    USE SIGNAL ;
    PORT
      LAYER met2 ;
        RECT 31.370 0.000 31.650 0.280 ;
    END
  END s_axi_araddr_9
  PIN s_axi_arready
    DIRECTION OUTPUT ;
    USE SIGNAL ;
    ANTENNAGATEAREA 0.434700 ;
    ANTENNADIFFAREA 1.137600 ;
    PORT
      LAYER met3 ;
        RECT 0.000 146.920 0.600 147.520 ;
    END
  END s_axi_arready
  PIN s_axi_arvalid
    DIRECTION INPUT ;
    USE SIGNAL ;
    ANTENNAGATEAREA 0.647700 ;
    ANTENNADIFFAREA 0.434700 ;
    PORT
      LAYER met3 ;
        RECT 0.000 142.840 0.600 143.440 ;
    END
  END s_axi_arvalid
  PIN s_axi_awaddr_0
    DIRECTION INPUT ;
    USE SIGNAL ;
    ANTENNAGATEAREA 0.647700 ;
    ANTENNADIFFAREA 0.434700 ;
    PORT
      LAYER met3 ;
        RECT 247.180 95.240 247.780 95.840 ;
    END
  END s_axi_awaddr_0
  PIN s_axi_awaddr_1
    DIRECTION INPUT ;
    USE SIGNAL ;
    ANTENNAGATEAREA 0.647700 ;
    ANTENNADIFFAREA 0.434700 ;
    PORT
      LAYER met2 ;
        RECT 202.490 0.000 202.770 0.280 ;
    END
  END s_axi_awaddr_1
  PIN s_axi_awaddr_10
    DIRECTION INPUT ;
    USE SIGNAL ;
    ANTENNAGATEAREA 0.647700 ;
    ANTENNADIFFAREA 0.434700 ;
    PORT
      LAYER met2 ;
        RECT 185.930 0.000 186.210 0.280 ;
    END
  END s_axi_awaddr_10
  PIN s_axi_awaddr_11
    DIRECTION INPUT ;
    USE SIGNAL ;
    ANTENNAGATEAREA 0.647700 ;
    ANTENNADIFFAREA 0.434700 ;
    PORT
      LAYER met2 ;
        RECT 143.610 0.000 143.890 0.280 ;
    END
  END s_axi_awaddr_11
  PIN s_axi_awaddr_12
    DIRECTION INPUT ;
    USE SIGNAL ;
    ANTENNAGATEAREA 0.647700 ;
    ANTENNADIFFAREA 0.434700 ;
    PORT
      LAYER met2 ;
        RECT 187.770 0.000 188.050 0.280 ;
    END
  END s_axi_awaddr_12
  PIN s_axi_awaddr_13
    DIRECTION INPUT ;
    USE SIGNAL ;
    ANTENNAGATEAREA 0.647700 ;
    ANTENNADIFFAREA 0.434700 ;
    PORT
      LAYER met2 ;
        RECT 81.050 0.000 81.330 0.280 ;
    END
  END s_axi_awaddr_13
  PIN s_axi_awaddr_14
    DIRECTION INPUT ;
    USE SIGNAL ;
    ANTENNAGATEAREA 0.647700 ;
    ANTENNADIFFAREA 0.434700 ;
    PORT
      LAYER met2 ;
        RECT 104.970 0.000 105.250 0.280 ;
    END
  END s_axi_awaddr_14
  PIN s_axi_awaddr_15
    DIRECTION INPUT ;
    USE SIGNAL ;
    ANTENNAGATEAREA 0.647700 ;
    ANTENNADIFFAREA 0.434700 ;
    PORT
      LAYER met2 ;
        RECT 138.090 0.000 138.370 0.280 ;
    END
  END s_axi_awaddr_15
  PIN s_axi_awaddr_16
    DIRECTION INPUT ;
    USE SIGNAL ;
    ANTENNAGATEAREA 0.647700 ;
    ANTENNADIFFAREA 0.434700 ;
    PORT
      LAYER met2 ;
        RECT 186.850 0.000 187.130 0.280 ;
    END
  END s_axi_awaddr_16
  PIN s_axi_awaddr_17
    DIRECTION INPUT ;
    USE SIGNAL ;
    ANTENNAGATEAREA 0.647700 ;
    ANTENNADIFFAREA 0.434700 ;
    PORT
      LAYER met2 ;
        RECT 116.010 0.000 116.290 0.280 ;
    END
  END s_axi_awaddr_17
  PIN s_axi_awaddr_18
    DIRECTION INPUT ;
    USE SIGNAL ;
    ANTENNAGATEAREA 0.647700 ;
    ANTENNADIFFAREA 0.434700 ;
    PORT
      LAYER met2 ;
        RECT 192.370 0.000 192.650 0.280 ;
    END
  END s_axi_awaddr_18
  PIN s_axi_awaddr_19
    DIRECTION INPUT ;
    USE SIGNAL ;
    ANTENNAGATEAREA 0.647700 ;
    ANTENNADIFFAREA 0.434700 ;
    PORT
      LAYER met2 ;
        RECT 201.570 0.000 201.850 0.280 ;
    END
  END s_axi_awaddr_19
  PIN s_axi_awaddr_2
    DIRECTION INPUT ;
    USE SIGNAL ;
    ANTENNAGATEAREA 0.647700 ;
    ANTENNADIFFAREA 0.434700 ;
    PORT
      LAYER met3 ;
        RECT 247.180 114.280 247.780 114.880 ;
    END
  END s_axi_awaddr_2
  PIN s_axi_awaddr_20
    DIRECTION INPUT ;
    USE SIGNAL ;
    ANTENNAGATEAREA 0.647700 ;
    ANTENNADIFFAREA 0.434700 ;
    PORT
      LAYER met2 ;
        RECT 113.250 0.000 113.530 0.280 ;
    END
  END s_axi_awaddr_20
  PIN s_axi_awaddr_21
    DIRECTION INPUT ;
    USE SIGNAL ;
    ANTENNAGATEAREA 0.647700 ;
    ANTENNADIFFAREA 0.434700 ;
    PORT
      LAYER met3 ;
        RECT 247.180 99.320 247.780 99.920 ;
    END
  END s_axi_awaddr_21
  PIN s_axi_awaddr_22
    DIRECTION INPUT ;
    USE SIGNAL ;
    ANTENNAGATEAREA 0.647700 ;
    ANTENNADIFFAREA 0.434700 ;
    PORT
      LAYER met2 ;
        RECT 121.530 0.000 121.810 0.280 ;
    END
  END s_axi_awaddr_22
  PIN s_axi_awaddr_23
    DIRECTION INPUT ;
    USE SIGNAL ;
    ANTENNAGATEAREA 0.647700 ;
    ANTENNADIFFAREA 0.434700 ;
    PORT
      LAYER met2 ;
        RECT 85.650 0.000 85.930 0.280 ;
    END
  END s_axi_awaddr_23
  PIN s_axi_awaddr_24
    DIRECTION INPUT ;
    USE SIGNAL ;
    ANTENNAGATEAREA 0.647700 ;
    ANTENNADIFFAREA 0.434700 ;
    PORT
      LAYER met2 ;
        RECT 81.970 0.000 82.250 0.280 ;
    END
  END s_axi_awaddr_24
  PIN s_axi_awaddr_25
    DIRECTION INPUT ;
    USE SIGNAL ;
    ANTENNAGATEAREA 0.647700 ;
    ANTENNADIFFAREA 0.434700 ;
    PORT
      LAYER met2 ;
        RECT 91.170 0.000 91.450 0.280 ;
    END
  END s_axi_awaddr_25
  PIN s_axi_awaddr_26
    DIRECTION INPUT ;
    USE SIGNAL ;
    ANTENNAGATEAREA 0.647700 ;
    ANTENNADIFFAREA 0.434700 ;
    PORT
      LAYER met3 ;
        RECT 0.000 108.840 0.600 109.440 ;
    END
  END s_axi_awaddr_26
  PIN s_axi_awaddr_27
    DIRECTION INPUT ;
    USE SIGNAL ;
    ANTENNAGATEAREA 0.647700 ;
    ANTENNADIFFAREA 0.434700 ;
    PORT
      LAYER met2 ;
        RECT 191.450 0.000 191.730 0.280 ;
    END
  END s_axi_awaddr_27
  PIN s_axi_awaddr_28
    DIRECTION INPUT ;
    USE SIGNAL ;
    ANTENNAGATEAREA 0.647700 ;
    ANTENNADIFFAREA 0.434700 ;
    PORT
      LAYER met3 ;
        RECT 0.000 121.080 0.600 121.680 ;
    END
  END s_axi_awaddr_28
  PIN s_axi_awaddr_29
    DIRECTION INPUT ;
    USE SIGNAL ;
    ANTENNAGATEAREA 0.647700 ;
    ANTENNADIFFAREA 0.434700 ;
    PORT
      LAYER met3 ;
        RECT 247.180 122.440 247.780 123.040 ;
    END
  END s_axi_awaddr_29
  PIN s_axi_awaddr_3
    DIRECTION INPUT ;
    USE SIGNAL ;
    ANTENNAGATEAREA 0.647700 ;
    ANTENNADIFFAREA 0.434700 ;
    PORT
      LAYER met3 ;
        RECT 247.180 97.960 247.780 98.560 ;
    END
  END s_axi_awaddr_3
  PIN s_axi_awaddr_30
    DIRECTION INPUT ;
    USE SIGNAL ;
    ANTENNAGATEAREA 0.647700 ;
    ANTENNADIFFAREA 0.434700 ;
    PORT
      LAYER met3 ;
        RECT 247.180 110.200 247.780 110.800 ;
    END
  END s_axi_awaddr_30
  PIN s_axi_awaddr_31
    DIRECTION INPUT ;
    USE SIGNAL ;
    ANTENNAGATEAREA 0.647700 ;
    ANTENNADIFFAREA 0.434700 ;
    PORT
      LAYER met3 ;
        RECT 247.180 125.160 247.780 125.760 ;
    END
  END s_axi_awaddr_31
  PIN s_axi_awaddr_4
    DIRECTION INPUT ;
    USE SIGNAL ;
    ANTENNAGATEAREA 0.647700 ;
    ANTENNADIFFAREA 0.434700 ;
    PORT
      LAYER met3 ;
        RECT 247.180 123.800 247.780 124.400 ;
    END
  END s_axi_awaddr_4
  PIN s_axi_awaddr_5
    DIRECTION INPUT ;
    USE SIGNAL ;
    ANTENNAGATEAREA 0.647700 ;
    ANTENNADIFFAREA 0.434700 ;
    PORT
      LAYER met2 ;
        RECT 208.930 0.000 209.210 0.280 ;
    END
  END s_axi_awaddr_5
  PIN s_axi_awaddr_6
    DIRECTION INPUT ;
    USE SIGNAL ;
    ANTENNAGATEAREA 0.647700 ;
    ANTENNADIFFAREA 0.434700 ;
    PORT
      LAYER met2 ;
        RECT 145.450 0.000 145.730 0.280 ;
    END
  END s_axi_awaddr_6
  PIN s_axi_awaddr_7
    DIRECTION INPUT ;
    USE SIGNAL ;
    ANTENNAGATEAREA 0.647700 ;
    ANTENNADIFFAREA 0.434700 ;
    PORT
      LAYER met2 ;
        RECT 209.850 0.000 210.130 0.280 ;
    END
  END s_axi_awaddr_7
  PIN s_axi_awaddr_8
    DIRECTION INPUT ;
    USE SIGNAL ;
    ANTENNAGATEAREA 0.647700 ;
    ANTENNADIFFAREA 0.434700 ;
    PORT
      LAYER met2 ;
        RECT 109.570 0.000 109.850 0.280 ;
    END
  END s_axi_awaddr_8
  PIN s_axi_awaddr_9
    DIRECTION INPUT ;
    USE SIGNAL ;
    ANTENNAGATEAREA 0.647700 ;
    ANTENNADIFFAREA 0.434700 ;
    PORT
      LAYER met2 ;
        RECT 83.810 0.000 84.090 0.280 ;
    END
  END s_axi_awaddr_9
  PIN s_axi_awready
    DIRECTION OUTPUT ;
    USE SIGNAL ;
    ANTENNAGATEAREA 0.434700 ;
    ANTENNADIFFAREA 1.137600 ;
    PORT
      LAYER met3 ;
        RECT 0.000 140.120 0.600 140.720 ;
    END
  END s_axi_awready
  PIN s_axi_awvalid
    DIRECTION INPUT ;
    USE SIGNAL ;
    ANTENNAGATEAREA 0.647700 ;
    ANTENNADIFFAREA 0.434700 ;
    PORT
      LAYER met3 ;
        RECT 0.000 131.960 0.600 132.560 ;
    END
  END s_axi_awvalid
  PIN s_axi_bready
    DIRECTION INPUT ;
    USE SIGNAL ;
    ANTENNAGATEAREA 0.647700 ;
    ANTENNADIFFAREA 0.434700 ;
    PORT
      LAYER met3 ;
        RECT 0.000 157.800 0.600 158.400 ;
    END
  END s_axi_bready
  PIN s_axi_bresp_0
    DIRECTION OUTPUT ;
    USE SIGNAL ;
    ANTENNAGATEAREA 0.434700 ;
    ANTENNADIFFAREA 0.434700 ;
    PORT
      LAYER met3 ;
        RECT 0.000 138.760 0.600 139.360 ;
    END
  END s_axi_bresp_0
  PIN s_axi_bresp_1
    DIRECTION OUTPUT ;
    USE SIGNAL ;
    ANTENNAGATEAREA 0.434700 ;
    ANTENNADIFFAREA 0.775300 ;
    PORT
      LAYER met3 ;
        RECT 0.000 137.400 0.600 138.000 ;
    END
  END s_axi_bresp_1
  PIN s_axi_bvalid
    DIRECTION OUTPUT ;
    USE SIGNAL ;
    ANTENNAGATEAREA 0.434700 ;
    ANTENNADIFFAREA 1.137600 ;
    PORT
      LAYER met3 ;
        RECT 0.000 159.160 0.600 159.760 ;
    END
  END s_axi_bvalid
  PIN s_axi_rdata_0
    DIRECTION OUTPUT ;
    USE SIGNAL ;
    ANTENNAGATEAREA 0.434700 ;
    ANTENNADIFFAREA 1.137600 ;
    PORT
      LAYER met3 ;
        RECT 0.000 70.760 0.600 71.360 ;
    END
  END s_axi_rdata_0
  PIN s_axi_rdata_1
    DIRECTION OUTPUT ;
    USE SIGNAL ;
    ANTENNAGATEAREA 0.434700 ;
    ANTENNADIFFAREA 1.137600 ;
    PORT
      LAYER met2 ;
        RECT 58.050 0.000 58.330 0.280 ;
    END
  END s_axi_rdata_1
  PIN s_axi_rdata_10
    DIRECTION OUTPUT ;
    USE SIGNAL ;
    ANTENNAGATEAREA 0.434700 ;
    ANTENNADIFFAREA 1.137600 ;
    PORT
      LAYER met2 ;
        RECT 60.810 0.000 61.090 0.280 ;
    END
  END s_axi_rdata_10
  PIN s_axi_rdata_11
    DIRECTION OUTPUT ;
    USE SIGNAL ;
    ANTENNAGATEAREA 0.434700 ;
    ANTENNADIFFAREA 1.137600 ;
    PORT
      LAYER met3 ;
        RECT 0.000 104.760 0.600 105.360 ;
    END
  END s_axi_rdata_11
  PIN s_axi_rdata_12
    DIRECTION OUTPUT ;
    USE SIGNAL ;
    ANTENNAGATEAREA 0.434700 ;
    ANTENNADIFFAREA 1.137600 ;
    PORT
      LAYER met3 ;
        RECT 0.000 133.320 0.600 133.920 ;
    END
  END s_axi_rdata_12
  PIN s_axi_rdata_13
    DIRECTION OUTPUT ;
    USE SIGNAL ;
    ANTENNAGATEAREA 0.434700 ;
    ANTENNADIFFAREA 1.137600 ;
    PORT
      LAYER met3 ;
        RECT 0.000 72.120 0.600 72.720 ;
    END
  END s_axi_rdata_13
  PIN s_axi_rdata_14
    DIRECTION OUTPUT ;
    USE SIGNAL ;
    ANTENNAGATEAREA 0.434700 ;
    ANTENNADIFFAREA 1.137600 ;
    PORT
      LAYER met2 ;
        RECT 34.130 0.000 34.410 0.280 ;
    END
  END s_axi_rdata_14
  PIN s_axi_rdata_15
    DIRECTION OUTPUT ;
    USE SIGNAL ;
    ANTENNAGATEAREA 0.434700 ;
    ANTENNADIFFAREA 1.137600 ;
    PORT
      LAYER met3 ;
        RECT 0.000 152.360 0.600 152.960 ;
    END
  END s_axi_rdata_15
  PIN s_axi_rdata_16
    DIRECTION OUTPUT ;
    USE SIGNAL ;
    ANTENNAGATEAREA 0.434700 ;
    ANTENNADIFFAREA 1.137600 ;
    PORT
      LAYER met2 ;
        RECT 52.530 0.000 52.810 0.280 ;
    END
  END s_axi_rdata_16
  PIN s_axi_rdata_17
    DIRECTION OUTPUT ;
    USE SIGNAL ;
    ANTENNAGATEAREA 0.434700 ;
    ANTENNADIFFAREA 1.137600 ;
    PORT
      LAYER met2 ;
        RECT 20.330 0.000 20.610 0.280 ;
    END
  END s_axi_rdata_17
  PIN s_axi_rdata_18
    DIRECTION OUTPUT ;
    USE SIGNAL ;
    ANTENNAGATEAREA 0.434700 ;
    ANTENNADIFFAREA 1.137600 ;
    PORT
      LAYER met3 ;
        RECT 0.000 127.880 0.600 128.480 ;
    END
  END s_axi_rdata_18
  PIN s_axi_rdata_19
    DIRECTION OUTPUT ;
    USE SIGNAL ;
    ANTENNAGATEAREA 0.434700 ;
    ANTENNADIFFAREA 1.137600 ;
    PORT
      LAYER met3 ;
        RECT 0.000 153.720 0.600 154.320 ;
    END
  END s_axi_rdata_19
  PIN s_axi_rdata_2
    DIRECTION OUTPUT ;
    USE SIGNAL ;
    ANTENNAGATEAREA 0.434700 ;
    ANTENNADIFFAREA 1.137600 ;
    PORT
      LAYER met3 ;
        RECT 0.000 54.440 0.600 55.040 ;
    END
  END s_axi_rdata_2
  PIN s_axi_rdata_20
    DIRECTION OUTPUT ;
    USE SIGNAL ;
    ANTENNAGATEAREA 0.434700 ;
    ANTENNADIFFAREA 1.137600 ;
    PORT
      LAYER met3 ;
        RECT 0.000 122.440 0.600 123.040 ;
    END
  END s_axi_rdata_20
  PIN s_axi_rdata_21
    DIRECTION OUTPUT ;
    USE SIGNAL ;
    ANTENNAGATEAREA 0.434700 ;
    ANTENNADIFFAREA 1.137600 ;
    PORT
      LAYER met2 ;
        RECT 38.730 0.000 39.010 0.280 ;
    END
  END s_axi_rdata_21
  PIN s_axi_rdata_22
    DIRECTION OUTPUT ;
    USE SIGNAL ;
    ANTENNAGATEAREA 0.434700 ;
    ANTENNADIFFAREA 1.137600 ;
    PORT
      LAYER met3 ;
        RECT 0.000 118.360 0.600 118.960 ;
    END
  END s_axi_rdata_22
  PIN s_axi_rdata_23
    DIRECTION OUTPUT ;
    USE SIGNAL ;
    ANTENNAGATEAREA 0.434700 ;
    ANTENNADIFFAREA 1.137600 ;
    PORT
      LAYER met3 ;
        RECT 0.000 107.480 0.600 108.080 ;
    END
  END s_axi_rdata_23
  PIN s_axi_rdata_24
    DIRECTION OUTPUT ;
    USE SIGNAL ;
    ANTENNAGATEAREA 0.434700 ;
    ANTENNADIFFAREA 1.137600 ;
    PORT
      LAYER met2 ;
        RECT 61.730 0.000 62.010 0.280 ;
    END
  END s_axi_rdata_24
  PIN s_axi_rdata_25
    DIRECTION OUTPUT ;
    USE SIGNAL ;
    ANTENNAGATEAREA 0.434700 ;
    ANTENNADIFFAREA 1.137600 ;
    PORT
      LAYER met3 ;
        RECT 0.000 76.200 0.600 76.800 ;
    END
  END s_axi_rdata_25
  PIN s_axi_rdata_26
    DIRECTION OUTPUT ;
    USE SIGNAL ;
    ANTENNAGATEAREA 0.434700 ;
    ANTENNADIFFAREA 1.137600 ;
    PORT
      LAYER met3 ;
        RECT 0.000 102.040 0.600 102.640 ;
    END
  END s_axi_rdata_26
  PIN s_axi_rdata_27
    DIRECTION OUTPUT ;
    USE SIGNAL ;
    ANTENNAGATEAREA 0.434700 ;
    ANTENNADIFFAREA 1.137600 ;
    PORT
      LAYER met3 ;
        RECT 0.000 114.280 0.600 114.880 ;
    END
  END s_axi_rdata_27
  PIN s_axi_rdata_28
    DIRECTION OUTPUT ;
    USE SIGNAL ;
    ANTENNAGATEAREA 0.434700 ;
    ANTENNADIFFAREA 1.137600 ;
    PORT
      LAYER met3 ;
        RECT 0.000 155.080 0.600 155.680 ;
    END
  END s_axi_rdata_28
  PIN s_axi_rdata_29
    DIRECTION OUTPUT ;
    USE SIGNAL ;
    ANTENNAGATEAREA 0.434700 ;
    ANTENNADIFFAREA 1.137600 ;
    PORT
      LAYER met3 ;
        RECT 0.000 92.520 0.600 93.120 ;
    END
  END s_axi_rdata_29
  PIN s_axi_rdata_3
    DIRECTION OUTPUT ;
    USE SIGNAL ;
    ANTENNAGATEAREA 0.434700 ;
    ANTENNADIFFAREA 1.137600 ;
    PORT
      LAYER met3 ;
        RECT 0.000 129.240 0.600 129.840 ;
    END
  END s_axi_rdata_3
  PIN s_axi_rdata_30
    DIRECTION OUTPUT ;
    USE SIGNAL ;
    ANTENNAGATEAREA 0.434700 ;
    ANTENNADIFFAREA 1.137600 ;
    PORT
      LAYER met3 ;
        RECT 0.000 62.600 0.600 63.200 ;
    END
  END s_axi_rdata_30
  PIN s_axi_rdata_31
    DIRECTION OUTPUT ;
    USE SIGNAL ;
    ANTENNAGATEAREA 0.434700 ;
    ANTENNADIFFAREA 1.137600 ;
    PORT
      LAYER met3 ;
        RECT 0.000 80.280 0.600 80.880 ;
    END
  END s_axi_rdata_31
  PIN s_axi_rdata_4
    DIRECTION OUTPUT ;
    USE SIGNAL ;
    ANTENNAGATEAREA 0.434700 ;
    ANTENNADIFFAREA 1.137600 ;
    PORT
      LAYER met3 ;
        RECT 0.000 38.120 0.600 38.720 ;
    END
  END s_axi_rdata_4
  PIN s_axi_rdata_5
    DIRECTION OUTPUT ;
    USE SIGNAL ;
    ANTENNAGATEAREA 0.434700 ;
    ANTENNADIFFAREA 1.137600 ;
    PORT
      LAYER met2 ;
        RECT 55.290 0.000 55.570 0.280 ;
    END
  END s_axi_rdata_5
  PIN s_axi_rdata_6
    DIRECTION OUTPUT ;
    USE SIGNAL ;
    ANTENNAGATEAREA 0.434700 ;
    ANTENNADIFFAREA 1.137600 ;
    PORT
      LAYER met3 ;
        RECT 0.000 89.800 0.600 90.400 ;
    END
  END s_axi_rdata_6
  PIN s_axi_rdata_7
    DIRECTION OUTPUT ;
    USE SIGNAL ;
    ANTENNAGATEAREA 0.434700 ;
    ANTENNADIFFAREA 1.137600 ;
    PORT
      LAYER met3 ;
        RECT 0.000 112.920 0.600 113.520 ;
    END
  END s_axi_rdata_7
  PIN s_axi_rdata_8
    DIRECTION OUTPUT ;
    USE SIGNAL ;
    ANTENNAGATEAREA 0.434700 ;
    ANTENNADIFFAREA 1.137600 ;
    PORT
      LAYER met3 ;
        RECT 0.000 84.360 0.600 84.960 ;
    END
  END s_axi_rdata_8
  PIN s_axi_rdata_9
    DIRECTION OUTPUT ;
    USE SIGNAL ;
    ANTENNAGATEAREA 0.434700 ;
    ANTENNADIFFAREA 1.137600 ;
    PORT
      LAYER met3 ;
        RECT 0.000 95.240 0.600 95.840 ;
    END
  END s_axi_rdata_9
  PIN s_axi_rready
    DIRECTION INPUT ;
    USE SIGNAL ;
    ANTENNAGATEAREA 0.647700 ;
    ANTENNADIFFAREA 0.434700 ;
    PORT
      LAYER met3 ;
        RECT 0.000 168.680 0.600 169.280 ;
    END
  END s_axi_rready
  PIN s_axi_rresp_0
    DIRECTION OUTPUT ;
    USE SIGNAL ;
    ANTENNAGATEAREA 0.434700 ;
    ANTENNADIFFAREA 0.775300 ;
    PORT
      LAYER met3 ;
        RECT 0.000 136.040 0.600 136.640 ;
    END
  END s_axi_rresp_0
  PIN s_axi_rresp_1
    DIRECTION OUTPUT ;
    USE SIGNAL ;
    ANTENNAGATEAREA 0.434700 ;
    ANTENNADIFFAREA 0.775300 ;
    PORT
      LAYER met3 ;
        RECT 0.000 134.680 0.600 135.280 ;
    END
  END s_axi_rresp_1
  PIN s_axi_rvalid
    DIRECTION OUTPUT ;
    USE SIGNAL ;
    ANTENNAGATEAREA 0.434700 ;
    ANTENNADIFFAREA 1.137600 ;
    PORT
      LAYER met3 ;
        RECT 0.000 171.400 0.600 172.000 ;
    END
  END s_axi_rvalid
  PIN s_axi_wdata_0
    DIRECTION INPUT ;
    USE SIGNAL ;
    ANTENNAGATEAREA 0.647700 ;
    ANTENNADIFFAREA 0.434700 ;
    PORT
      LAYER met2 ;
        RECT 175.810 258.220 176.090 258.500 ;
    END
  END s_axi_wdata_0
  PIN s_axi_wdata_1
    DIRECTION INPUT ;
    USE SIGNAL ;
    ANTENNAGATEAREA 0.647700 ;
    ANTENNADIFFAREA 0.434700 ;
    PORT
      LAYER met2 ;
        RECT 116.010 258.220 116.290 258.500 ;
    END
  END s_axi_wdata_1
  PIN s_axi_wdata_10
    DIRECTION INPUT ;
    USE SIGNAL ;
    ANTENNAGATEAREA 0.647700 ;
    ANTENNADIFFAREA 0.434700 ;
    PORT
      LAYER met2 ;
        RECT 203.410 258.220 203.690 258.500 ;
    END
  END s_axi_wdata_10
  PIN s_axi_wdata_11
    DIRECTION INPUT ;
    USE SIGNAL ;
    ANTENNAGATEAREA 0.647700 ;
    ANTENNADIFFAREA 0.434700 ;
    PORT
      LAYER met2 ;
        RECT 119.690 258.220 119.970 258.500 ;
    END
  END s_axi_wdata_11
  PIN s_axi_wdata_12
    DIRECTION INPUT ;
    USE SIGNAL ;
    ANTENNAGATEAREA 0.647700 ;
    ANTENNADIFFAREA 0.434700 ;
    PORT
      LAYER met3 ;
        RECT 247.180 144.200 247.780 144.800 ;
    END
  END s_axi_wdata_12
  PIN s_axi_wdata_13
    DIRECTION INPUT ;
    USE SIGNAL ;
    ANTENNAGATEAREA 0.647700 ;
    ANTENNADIFFAREA 0.434700 ;
    PORT
      LAYER met2 ;
        RECT 139.010 258.220 139.290 258.500 ;
    END
  END s_axi_wdata_13
  PIN s_axi_wdata_14
    DIRECTION INPUT ;
    USE SIGNAL ;
    ANTENNAGATEAREA 0.647700 ;
    ANTENNADIFFAREA 0.434700 ;
    PORT
      LAYER met2 ;
        RECT 192.370 258.220 192.650 258.500 ;
    END
  END s_axi_wdata_14
  PIN s_axi_wdata_15
    DIRECTION INPUT ;
    USE SIGNAL ;
    ANTENNAGATEAREA 0.647700 ;
    ANTENNADIFFAREA 0.434700 ;
    PORT
      LAYER met2 ;
        RECT 151.890 258.220 152.170 258.500 ;
    END
  END s_axi_wdata_15
  PIN s_axi_wdata_16
    DIRECTION INPUT ;
    USE SIGNAL ;
    ANTENNAGATEAREA 0.647700 ;
    ANTENNADIFFAREA 0.434700 ;
    PORT
      LAYER met3 ;
        RECT 247.180 148.280 247.780 148.880 ;
    END
  END s_axi_wdata_16
  PIN s_axi_wdata_17
    DIRECTION INPUT ;
    USE SIGNAL ;
    ANTENNAGATEAREA 0.647700 ;
    ANTENNADIFFAREA 0.434700 ;
    PORT
      LAYER met3 ;
        RECT 247.180 202.680 247.780 203.280 ;
    END
  END s_axi_wdata_17
  PIN s_axi_wdata_18
    DIRECTION INPUT ;
    USE SIGNAL ;
    ANTENNAGATEAREA 0.647700 ;
    ANTENNADIFFAREA 0.434700 ;
    PORT
      LAYER met3 ;
        RECT 247.180 146.920 247.780 147.520 ;
    END
  END s_axi_wdata_18
  PIN s_axi_wdata_19
    DIRECTION INPUT ;
    USE SIGNAL ;
    ANTENNAGATEAREA 0.647700 ;
    ANTENNADIFFAREA 0.434700 ;
    PORT
      LAYER met2 ;
        RECT 166.610 258.220 166.890 258.500 ;
    END
  END s_axi_wdata_19
  PIN s_axi_wdata_2
    DIRECTION INPUT ;
    USE SIGNAL ;
    ANTENNAGATEAREA 0.647700 ;
    ANTENNADIFFAREA 0.434700 ;
    PORT
      LAYER met3 ;
        RECT 247.180 171.400 247.780 172.000 ;
    END
  END s_axi_wdata_2
  PIN s_axi_wdata_20
    DIRECTION INPUT ;
    USE SIGNAL ;
    ANTENNAGATEAREA 0.647700 ;
    ANTENNADIFFAREA 0.434700 ;
    PORT
      LAYER met2 ;
        RECT 131.650 258.220 131.930 258.500 ;
    END
  END s_axi_wdata_20
  PIN s_axi_wdata_21
    DIRECTION INPUT ;
    USE SIGNAL ;
    ANTENNAGATEAREA 0.647700 ;
    ANTENNADIFFAREA 0.434700 ;
    PORT
      LAYER met2 ;
        RECT 158.330 258.220 158.610 258.500 ;
    END
  END s_axi_wdata_21
  PIN s_axi_wdata_22
    DIRECTION INPUT ;
    USE SIGNAL ;
    ANTENNAGATEAREA 0.647700 ;
    ANTENNADIFFAREA 0.434700 ;
    PORT
      LAYER met3 ;
        RECT 0.000 151.000 0.600 151.600 ;
    END
  END s_axi_wdata_22
  PIN s_axi_wdata_23
    DIRECTION INPUT ;
    USE SIGNAL ;
    ANTENNAGATEAREA 0.647700 ;
    ANTENNADIFFAREA 0.434700 ;
    PORT
      LAYER met2 ;
        RECT 144.530 258.220 144.810 258.500 ;
    END
  END s_axi_wdata_23
  PIN s_axi_wdata_24
    DIRECTION INPUT ;
    USE SIGNAL ;
    ANTENNAGATEAREA 0.647700 ;
    ANTENNADIFFAREA 0.434700 ;
    PORT
      LAYER met2 ;
        RECT 132.570 258.220 132.850 258.500 ;
    END
  END s_axi_wdata_24
  PIN s_axi_wdata_25
    DIRECTION INPUT ;
    USE SIGNAL ;
    ANTENNAGATEAREA 0.647700 ;
    ANTENNADIFFAREA 0.434700 ;
    PORT
      LAYER met2 ;
        RECT 182.250 258.220 182.530 258.500 ;
    END
  END s_axi_wdata_25
  PIN s_axi_wdata_26
    DIRECTION INPUT ;
    USE SIGNAL ;
    ANTENNAGATEAREA 0.647700 ;
    ANTENNADIFFAREA 0.434700 ;
    PORT
      LAYER met2 ;
        RECT 100.370 258.220 100.650 258.500 ;
    END
  END s_axi_wdata_26
  PIN s_axi_wdata_27
    DIRECTION INPUT ;
    USE SIGNAL ;
    ANTENNAGATEAREA 0.647700 ;
    ANTENNADIFFAREA 0.434700 ;
    PORT
      LAYER met2 ;
        RECT 161.090 258.220 161.370 258.500 ;
    END
  END s_axi_wdata_27
  PIN s_axi_wdata_28
    DIRECTION INPUT ;
    USE SIGNAL ;
    ANTENNAGATEAREA 0.647700 ;
    ANTENNADIFFAREA 0.434700 ;
    PORT
      LAYER met2 ;
        RECT 99.450 258.220 99.730 258.500 ;
    END
  END s_axi_wdata_28
  PIN s_axi_wdata_29
    DIRECTION INPUT ;
    USE SIGNAL ;
    ANTENNAGATEAREA 0.647700 ;
    ANTENNADIFFAREA 0.434700 ;
    PORT
      LAYER met2 ;
        RECT 59.890 258.220 60.170 258.500 ;
    END
  END s_axi_wdata_29
  PIN s_axi_wdata_3
    DIRECTION INPUT ;
    USE SIGNAL ;
    ANTENNAGATEAREA 0.647700 ;
    ANTENNADIFFAREA 0.434700 ;
    PORT
      LAYER met3 ;
        RECT 0.000 172.760 0.600 173.360 ;
    END
  END s_axi_wdata_3
  PIN s_axi_wdata_30
    DIRECTION INPUT ;
    USE SIGNAL ;
    ANTENNAGATEAREA 0.647700 ;
    ANTENNADIFFAREA 0.434700 ;
    PORT
      LAYER met2 ;
        RECT 57.130 258.220 57.410 258.500 ;
    END
  END s_axi_wdata_30
  PIN s_axi_wdata_31
    DIRECTION INPUT ;
    USE SIGNAL ;
    ANTENNAGATEAREA 0.647700 ;
    ANTENNADIFFAREA 0.434700 ;
    PORT
      LAYER met3 ;
        RECT 0.000 170.040 0.600 170.640 ;
    END
  END s_axi_wdata_31
  PIN s_axi_wdata_4
    DIRECTION INPUT ;
    USE SIGNAL ;
    ANTENNAGATEAREA 0.647700 ;
    ANTENNADIFFAREA 0.434700 ;
    PORT
      LAYER met3 ;
        RECT 247.180 174.120 247.780 174.720 ;
    END
  END s_axi_wdata_4
  PIN s_axi_wdata_5
    DIRECTION INPUT ;
    USE SIGNAL ;
    ANTENNAGATEAREA 0.647700 ;
    ANTENNADIFFAREA 0.434700 ;
    PORT
      LAYER met2 ;
        RECT 190.530 258.220 190.810 258.500 ;
    END
  END s_axi_wdata_5
  PIN s_axi_wdata_6
    DIRECTION INPUT ;
    USE SIGNAL ;
    ANTENNAGATEAREA 0.647700 ;
    ANTENNADIFFAREA 0.434700 ;
    PORT
      LAYER met2 ;
        RECT 110.490 258.220 110.770 258.500 ;
    END
  END s_axi_wdata_6
  PIN s_axi_wdata_7
    DIRECTION INPUT ;
    USE SIGNAL ;
    ANTENNAGATEAREA 0.647700 ;
    ANTENNADIFFAREA 0.434700 ;
    PORT
      LAYER met3 ;
        RECT 247.180 151.000 247.780 151.600 ;
    END
  END s_axi_wdata_7
  PIN s_axi_wdata_8
    DIRECTION INPUT ;
    USE SIGNAL ;
    ANTENNAGATEAREA 0.647700 ;
    ANTENNADIFFAREA 0.434700 ;
    PORT
      LAYER met2 ;
        RECT 58.050 258.220 58.330 258.500 ;
    END
  END s_axi_wdata_8
  PIN s_axi_wdata_9
    DIRECTION INPUT ;
    USE SIGNAL ;
    ANTENNAGATEAREA 0.647700 ;
    ANTENNADIFFAREA 0.434700 ;
    PORT
      LAYER met2 ;
        RECT 216.290 258.220 216.570 258.500 ;
    END
  END s_axi_wdata_9
  PIN s_axi_wready
    DIRECTION OUTPUT ;
    USE SIGNAL ;
    ANTENNAGATEAREA 0.434700 ;
    ANTENNADIFFAREA 1.137600 ;
    PORT
      LAYER met3 ;
        RECT 0.000 144.200 0.600 144.800 ;
    END
  END s_axi_wready
  PIN s_axi_wstrb_0
    DIRECTION INPUT ;
    USE SIGNAL ;
    ANTENNAGATEAREA 0.647700 ;
    ANTENNADIFFAREA 0.434700 ;
    PORT
      LAYER met2 ;
        RECT 53.450 258.220 53.730 258.500 ;
    END
  END s_axi_wstrb_0
  PIN s_axi_wstrb_1
    DIRECTION INPUT ;
    USE SIGNAL ;
    ANTENNAGATEAREA 0.647700 ;
    ANTENNADIFFAREA 0.434700 ;
    PORT
      LAYER met2 ;
        RECT 55.290 258.220 55.570 258.500 ;
    END
  END s_axi_wstrb_1
  PIN s_axi_wstrb_2
    DIRECTION INPUT ;
    USE SIGNAL ;
    ANTENNAGATEAREA 0.647700 ;
    ANTENNADIFFAREA 0.434700 ;
    PORT
      LAYER met2 ;
        RECT 56.210 258.220 56.490 258.500 ;
    END
  END s_axi_wstrb_2
  PIN s_axi_wstrb_3
    DIRECTION INPUT ;
    USE SIGNAL ;
    ANTENNAGATEAREA 0.647700 ;
    ANTENNADIFFAREA 0.434700 ;
    PORT
      LAYER met3 ;
        RECT 0.000 167.320 0.600 167.920 ;
    END
  END s_axi_wstrb_3
  PIN s_axi_wvalid
    DIRECTION INPUT ;
    USE SIGNAL ;
    ANTENNAGATEAREA 0.647700 ;
    ANTENNADIFFAREA 0.434700 ;
    PORT
      LAYER met3 ;
        RECT 0.000 141.480 0.600 142.080 ;
    END
  END s_axi_wvalid
  OBS
      LAYER nwell ;
        RECT 5.330 10.795 242.150 247.710 ;
      LAYER li1 ;
        RECT 5.520 10.795 241.960 247.605 ;
      LAYER met1 ;
        RECT 5.520 10.240 241.960 247.760 ;
      LAYER met2 ;
        RECT 5.610 257.940 38.450 258.220 ;
        RECT 39.290 257.940 39.370 258.220 ;
        RECT 40.210 257.940 40.290 258.220 ;
        RECT 41.130 257.940 41.210 258.220 ;
        RECT 42.050 257.940 53.170 258.220 ;
        RECT 54.010 257.940 54.090 258.220 ;
        RECT 54.930 257.940 55.010 258.220 ;
        RECT 55.850 257.940 55.930 258.220 ;
        RECT 56.770 257.940 56.850 258.220 ;
        RECT 57.690 257.940 57.770 258.220 ;
        RECT 58.610 257.940 58.690 258.220 ;
        RECT 59.530 257.940 59.610 258.220 ;
        RECT 60.450 257.940 60.530 258.220 ;
        RECT 61.370 257.940 96.410 258.220 ;
        RECT 97.250 257.940 99.170 258.220 ;
        RECT 100.010 257.940 100.090 258.220 ;
        RECT 100.930 257.940 110.210 258.220 ;
        RECT 111.050 257.940 112.050 258.220 ;
        RECT 112.890 257.940 115.730 258.220 ;
        RECT 116.570 257.940 116.650 258.220 ;
        RECT 117.490 257.940 119.410 258.220 ;
        RECT 120.250 257.940 121.250 258.220 ;
        RECT 122.090 257.940 130.450 258.220 ;
        RECT 131.290 257.940 131.370 258.220 ;
        RECT 132.210 257.940 132.290 258.220 ;
        RECT 133.130 257.940 134.130 258.220 ;
        RECT 134.970 257.940 135.970 258.220 ;
        RECT 136.810 257.940 138.730 258.220 ;
        RECT 139.570 257.940 143.330 258.220 ;
        RECT 144.170 257.940 144.250 258.220 ;
        RECT 145.090 257.940 150.690 258.220 ;
        RECT 151.530 257.940 151.610 258.220 ;
        RECT 152.450 257.940 155.290 258.220 ;
        RECT 156.130 257.940 158.050 258.220 ;
        RECT 158.890 257.940 158.970 258.220 ;
        RECT 159.810 257.940 160.810 258.220 ;
        RECT 161.650 257.940 165.410 258.220 ;
        RECT 166.250 257.940 166.330 258.220 ;
        RECT 167.170 257.940 174.610 258.220 ;
        RECT 175.450 257.940 175.530 258.220 ;
        RECT 176.370 257.940 181.050 258.220 ;
        RECT 181.890 257.940 181.970 258.220 ;
        RECT 182.810 257.940 189.330 258.220 ;
        RECT 190.170 257.940 190.250 258.220 ;
        RECT 191.090 257.940 191.170 258.220 ;
        RECT 192.010 257.940 192.090 258.220 ;
        RECT 192.930 257.940 202.210 258.220 ;
        RECT 203.050 257.940 203.130 258.220 ;
        RECT 203.970 257.940 216.010 258.220 ;
        RECT 216.850 257.940 227.050 258.220 ;
        RECT 227.890 257.940 241.870 258.220 ;
        RECT 5.610 0.560 241.870 257.940 ;
        RECT 6.170 0.280 6.250 0.560 ;
        RECT 7.090 0.280 7.170 0.560 ;
        RECT 8.010 0.280 8.090 0.560 ;
        RECT 8.930 0.280 9.010 0.560 ;
        RECT 9.850 0.280 9.930 0.560 ;
        RECT 10.770 0.280 10.850 0.560 ;
        RECT 11.690 0.280 11.770 0.560 ;
        RECT 12.610 0.280 12.690 0.560 ;
        RECT 13.530 0.280 13.610 0.560 ;
        RECT 14.450 0.280 14.530 0.560 ;
        RECT 15.370 0.280 15.450 0.560 ;
        RECT 16.290 0.280 16.370 0.560 ;
        RECT 17.210 0.280 17.290 0.560 ;
        RECT 18.130 0.280 18.210 0.560 ;
        RECT 19.050 0.280 19.130 0.560 ;
        RECT 19.970 0.280 20.050 0.560 ;
        RECT 20.890 0.280 20.970 0.560 ;
        RECT 21.810 0.280 21.890 0.560 ;
        RECT 22.730 0.280 22.810 0.560 ;
        RECT 23.650 0.280 23.730 0.560 ;
        RECT 24.570 0.280 24.650 0.560 ;
        RECT 25.490 0.280 25.570 0.560 ;
        RECT 26.410 0.280 26.490 0.560 ;
        RECT 27.330 0.280 27.410 0.560 ;
        RECT 28.250 0.280 28.330 0.560 ;
        RECT 29.170 0.280 29.250 0.560 ;
        RECT 30.090 0.280 30.170 0.560 ;
        RECT 31.010 0.280 31.090 0.560 ;
        RECT 31.930 0.280 32.010 0.560 ;
        RECT 32.850 0.280 33.850 0.560 ;
        RECT 34.690 0.280 34.770 0.560 ;
        RECT 35.610 0.280 38.450 0.560 ;
        RECT 39.290 0.280 39.370 0.560 ;
        RECT 40.210 0.280 51.330 0.560 ;
        RECT 52.170 0.280 52.250 0.560 ;
        RECT 53.090 0.280 55.010 0.560 ;
        RECT 55.850 0.280 55.930 0.560 ;
        RECT 56.770 0.280 56.850 0.560 ;
        RECT 57.690 0.280 57.770 0.560 ;
        RECT 58.610 0.280 58.690 0.560 ;
        RECT 59.530 0.280 59.610 0.560 ;
        RECT 60.450 0.280 60.530 0.560 ;
        RECT 61.370 0.280 61.450 0.560 ;
        RECT 62.290 0.280 74.330 0.560 ;
        RECT 75.170 0.280 76.170 0.560 ;
        RECT 77.010 0.280 77.090 0.560 ;
        RECT 77.930 0.280 80.770 0.560 ;
        RECT 81.610 0.280 81.690 0.560 ;
        RECT 82.530 0.280 82.610 0.560 ;
        RECT 83.450 0.280 83.530 0.560 ;
        RECT 84.370 0.280 85.370 0.560 ;
        RECT 86.210 0.280 86.290 0.560 ;
        RECT 87.130 0.280 90.890 0.560 ;
        RECT 91.730 0.280 103.770 0.560 ;
        RECT 104.610 0.280 104.690 0.560 ;
        RECT 105.530 0.280 109.290 0.560 ;
        RECT 110.130 0.280 110.210 0.560 ;
        RECT 111.050 0.280 111.130 0.560 ;
        RECT 111.970 0.280 112.970 0.560 ;
        RECT 113.810 0.280 115.730 0.560 ;
        RECT 116.570 0.280 116.650 0.560 ;
        RECT 117.490 0.280 121.250 0.560 ;
        RECT 122.090 0.280 122.170 0.560 ;
        RECT 123.010 0.280 135.970 0.560 ;
        RECT 136.810 0.280 137.810 0.560 ;
        RECT 138.650 0.280 140.570 0.560 ;
        RECT 141.410 0.280 143.330 0.560 ;
        RECT 144.170 0.280 144.250 0.560 ;
        RECT 145.090 0.280 145.170 0.560 ;
        RECT 146.010 0.280 185.650 0.560 ;
        RECT 186.490 0.280 186.570 0.560 ;
        RECT 187.410 0.280 187.490 0.560 ;
        RECT 188.330 0.280 188.410 0.560 ;
        RECT 189.250 0.280 189.330 0.560 ;
        RECT 190.170 0.280 190.250 0.560 ;
        RECT 191.090 0.280 191.170 0.560 ;
        RECT 192.010 0.280 192.090 0.560 ;
        RECT 192.930 0.280 193.010 0.560 ;
        RECT 193.850 0.280 193.930 0.560 ;
        RECT 194.770 0.280 200.370 0.560 ;
        RECT 201.210 0.280 201.290 0.560 ;
        RECT 202.130 0.280 202.210 0.560 ;
        RECT 203.050 0.280 203.130 0.560 ;
        RECT 203.970 0.280 208.650 0.560 ;
        RECT 209.490 0.280 209.570 0.560 ;
        RECT 210.410 0.280 213.250 0.560 ;
        RECT 214.090 0.280 241.870 0.560 ;
      LAYER met3 ;
        RECT 0.600 237.680 247.180 247.685 ;
        RECT 1.000 234.920 247.180 237.680 ;
        RECT 0.600 203.680 247.180 234.920 ;
        RECT 0.600 200.920 246.780 203.680 ;
        RECT 0.600 176.480 247.180 200.920 ;
        RECT 1.000 171.000 246.780 176.480 ;
        RECT 1.000 166.920 247.180 171.000 ;
        RECT 0.600 165.600 247.180 166.920 ;
        RECT 1.000 164.200 247.180 165.600 ;
        RECT 0.600 161.520 247.180 164.200 ;
        RECT 1.000 152.000 247.180 161.520 ;
        RECT 1.000 141.080 246.780 152.000 ;
        RECT 1.000 128.880 247.180 141.080 ;
        RECT 1.000 120.680 246.780 128.880 ;
        RECT 1.000 119.360 247.180 120.680 ;
        RECT 1.000 113.880 246.780 119.360 ;
        RECT 1.000 111.200 247.180 113.880 ;
        RECT 1.000 109.800 246.780 111.200 ;
        RECT 1.000 103.040 247.180 109.800 ;
        RECT 1.000 100.280 246.780 103.040 ;
        RECT 0.600 96.240 246.780 100.280 ;
        RECT 1.000 94.840 246.780 96.240 ;
        RECT 1.000 88.040 247.180 94.840 ;
        RECT 0.600 85.360 247.180 88.040 ;
        RECT 1.000 82.600 247.180 85.360 ;
        RECT 0.600 81.280 247.180 82.600 ;
        RECT 1.000 79.920 247.180 81.280 ;
        RECT 1.000 78.520 246.780 79.920 ;
        RECT 0.600 77.200 247.180 78.520 ;
        RECT 1.000 69.000 247.180 77.200 ;
        RECT 0.600 63.600 247.180 69.000 ;
        RECT 1.000 60.840 247.180 63.600 ;
        RECT 0.600 55.440 247.180 60.840 ;
        RECT 1.000 52.680 247.180 55.440 ;
        RECT 0.600 41.840 247.180 52.680 ;
        RECT 1.000 40.440 247.180 41.840 ;
        RECT 0.600 39.120 247.180 40.440 ;
        RECT 1.000 37.720 247.180 39.120 ;
        RECT 0.600 10.715 247.180 37.720 ;
      LAYER met4 ;
        RECT 138.295 186.495 139.545 243.265 ;
  END
END axi_slave_adapter
END LIBRARY

